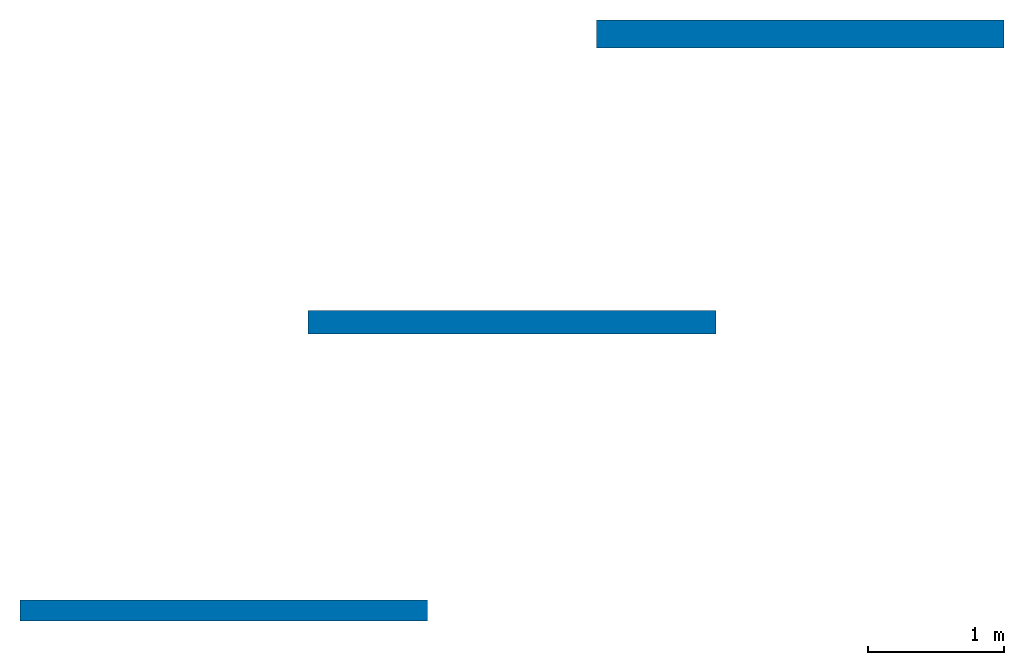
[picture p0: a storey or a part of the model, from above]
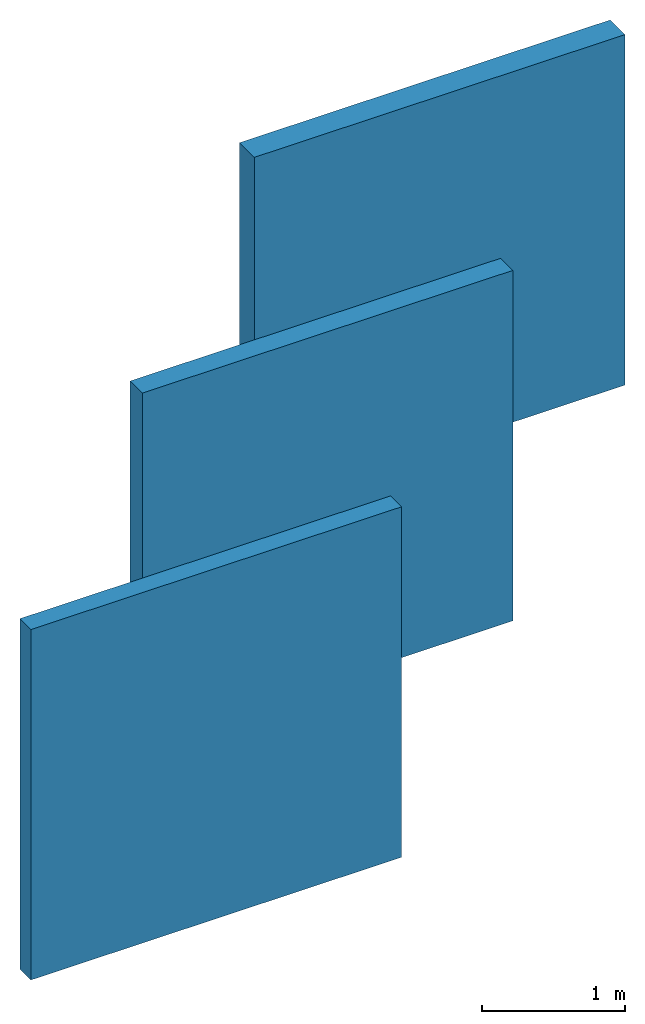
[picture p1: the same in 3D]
Properties of the parts of a building model (IFC2X3)

# File
Description: ViewDefinition [CoordinationView_V2.0, QuantityTakeOffAddOnView]
Time: 2021-05-19T20:20:58
Written by: The EXPRESS Data Manager Version 5.02.0100.07 : 28 Aug 2013
Made in: 20190108_1515(x64) - Exporter 19.1.0.0 - Alternate UI 19.1.0.0
Comment: STEP Physical File produced by: The EXPRESS Data Manager Version 5.02.0100.07 : 28 Aug 2013 * Module: EDMstepFileFactory/EDMstandAlone * Creation date: Wed May 19 20:20:58 2021 * Host: lt-026 * Database: C:\Users\WF2BF~1.POE\AppData\Local\Temp\{6B979DAE-2628-44FD-B715-F7CA476B2B23}\ifc * Database version: 5507 * Database creation date: Wed May 19 20:20:58 2021 * Schema: IFC2X3 * Model: DataRepository.ifc * Model creation date: Wed May 19 20:20:58 2021 * Header model: DataRepository.ifc_HeaderModel * Header model creation date: Wed May 19 20:20:58 2021 * EDMuser: sdai-user * EDMgroup: sdai-group * License ID and type: 5605 : Permanent license. Expiry date: * EDMstepFileFactory options: 020000

# IfcSite, Default
RefLatitude: 42, 24, 53, 508911; RefLongitude: -71, -15, -29, -58837; RefElevation: 0 mm
Other - Category: Project Information

# IfcBuilding
Pset_BuildingCommon - NumberOfStoreys: 1
Pset_ProductRequirements - Category: Project Information; sets with these values: 2

# IfcBuildingStorey: Level:NL_00_niveau, Begane grond
LongName: Begane grond; Elevation: 0 mm
Other(Type) - Category: Levels; Family Name: Level
Pset_AirSideSystemInformation - Name: Begane grond
Pset_ProductRequirements - Name: Begane grond; Category: Levels
Constraints - Elevation: 0 mm
Dimensions - Computation Height: 0 mm
Identity Data - Structural: no; Building Story: yes; Name: Begane grond
Other - Category: Levels; Family: Level: NL_00_niveau; Family and Type: Level: NL_00_niveau; Type: Level: NL_00_niveau; Type Id: Level: NL_00_niveau
Constraints(Type) - Elevation Base: Project Base Point
Graphics(Type) - Color: 16711680; Line Pattern: NL_00_niveau; Line Weight: 1; Symbol: NLRS_00_LAB_niveau bovenkant_gen_cadix: 1.8mm; Symbol at End 1 Default: no; Symbol at End 2 Default: yes
Identity Data(Type) - Type Name: NL_00_niveau

# IfcWallStandardCase: Basic Wall:NLRS_22_WA_Supafil Cavity XL_Spouwbreedte_154mm, Basic Wall:NLRS_22_WA_Supafil Cavity XL_Spouwbreedte_154mm:2470
In: Begane grond
Type - PredefinedType: STANDARD; Material: Knauf Insulation_inblaaswol Supafil Cavity XL 154 mm
Type - Analytical Properties - Absorptance: 0.1; Heat Transfer Coefficient (U): 0.24026; Roughness: 1; Thermal mass: 4533.76; Thermal Resistance (R): 4.16216
Type - Construction - Function: Exterior; Width: 154 mm; Wrapping at Inserts: Do not wrap
Type - Graphics - Coarse Scale Fill Color: 0
Type - Identity Data - Assembly Code: 22; Assembly Description: Binnenwanden; Description: Supafill Cavity XL; Manufacturer: Knauf Insulation B.V.; Model: Inblaas glaswol voor nieuwbouw woningen; Type Image: Raster image: SupafilCavityXL.png (2); Type Name: NLRS_22_WA_Supafil Cavity XL_Spouwbreedte_154mm; URL: www.knaufinsulation.nl
Type - Other - Category: Walls; Family Name: Basic Wall
Type - Pset_ElementShading - Roughness: 304.8 mm
Type - Pset_ManufacturerTypeInformation - Manufacturer: Knauf Insulation B.V.
Type - Pset_ProductRequirements - Category: Walls
Type - Pset_QuantityTakeOff - Reference: NLRS_22_WA_Supafil Cavity XL_Spouwbreedte_154mm
Type - Pset_ReinforcementBarPitchOfWall - Description: Supafill Cavity XL; Reference: NLRS_22_WA_Supafil Cavity XL_Spouwbreedte_154mm
Type - Pset_WallCommon - Reference: NLRS_22_WA_Supafil Cavity XL_Spouwbreedte_154mm; ThermalTransmittance: 0.24026 kg/K/s3; IsExternal: no
Classification: 22 Binnenwanden (Uniformat)
BaseQuantities - Height: 3000 mm; Length: 3000 mm; Width: 154 mm; GrossFootprintArea: 0.462 m2; NetVolume: 1386000000 m3; NetSideArea: 9000000 m2
Constraints - Base Constraint: Level: Begane grond; Base Extension Distance: 0 mm; Base is Attached: no; Base Offset: 0 mm; Location Line: Wall Centerline; Related to Mass: no; Room Bounding: yes; Top Constraint: Level: Hoogte; Top Extension Distance: 0 mm; Top is Attached: no; Top Offset: 0 mm; Unconnected Height: 3000 mm
Dimensions - Area: 9 m2; Length: 3000 mm; Volume: 1.386 m3
Other - Family: Basic Wall: NLRS_22_WA_Supafil Cavity XL_Spouwbreedte_154mm; Family and Type: Basic Wall: NLRS_22_WA_Supafil Cavity XL_Spouwbreedte_154mm; Type: Basic Wall: NLRS_22_WA_Supafil Cavity XL_Spouwbreedte_154mm; Type Id: Basic Wall: NLRS_22_WA_Supafil Cavity XL_Spouwbreedte_154mm
Phasing - Phase Created: New Construction
Structural - Enable Analytical Model: no; Structural: no; Structural Usage: Non-bearing
Pset_WallCommon - IsExternal: yes; ExtendToStructure: no; LoadBearing: no

# IfcWallStandardCase: Basic Wall:NLRS_22_WA_Supafil Cavity XL_Spouwbreedte_171mm, Basic Wall:NLRS_22_WA_Supafil Cavity XL_Spouwbreedte_171mm:3578
In: Begane grond
Type - PredefinedType: STANDARD; Material: Knauf Insulation_inblaaswol Supafil Cavity XL 171 mm
Type - Analytical Properties - Roughness: 1; Absorptance: 0.1; Heat Transfer Coefficient (U): 0.216374; Thermal mass: 5034.24; Thermal Resistance (R): 4.62162
Type - Construction - Function: Exterior; Wrapping at Inserts: Do not wrap; Width: 171 mm
Type - Graphics - Coarse Scale Fill Color: 0
Type - Identity Data - Type Image: Raster image: SupafilCavityXL.png (2); Assembly Code: 22; Assembly Description: Binnenwanden; Description: Supafill Cavity XL; Manufacturer: Knauf Insulation B.V.; Model: Inblaas glaswol voor nieuwbouw woningen; Type Name: NLRS_22_WA_Supafil Cavity XL_Spouwbreedte_171mm; URL: www.knaufinsulation.nl
Type - Other - Category: Walls; Family Name: Basic Wall
Type - Pset_ElementShading - Roughness: 304.8 mm
Type - Pset_ManufacturerTypeInformation - Manufacturer: Knauf Insulation B.V.
Type - Pset_ProductRequirements - Category: Walls
Type - Pset_QuantityTakeOff - Reference: NLRS_22_WA_Supafil Cavity XL_Spouwbreedte_171mm
Type - Pset_ReinforcementBarPitchOfWall - Description: Supafill Cavity XL; Reference: NLRS_22_WA_Supafil Cavity XL_Spouwbreedte_171mm
Type - Pset_WallCommon - IsExternal: no; Reference: NLRS_22_WA_Supafil Cavity XL_Spouwbreedte_171mm; ThermalTransmittance: 0.216374 kg/K/s3
Classification: 22 Binnenwanden (Uniformat)
BaseQuantities - Height: 3000 mm; Length: 3000 mm; Width: 171 mm; GrossFootprintArea: 0.513 m2; NetVolume: 1539000000 m3; NetSideArea: 9000000 m2
Constraints - Base Constraint: Level: Begane grond; Base Extension Distance: 0 mm; Base is Attached: no; Base Offset: 0 mm; Location Line: Wall Centerline; Related to Mass: no; Room Bounding: yes; Top Constraint: Level: Hoogte; Top Extension Distance: 0 mm; Top is Attached: no; Top Offset: 0 mm; Unconnected Height: 3000 mm
Dimensions - Area: 9 m2; Length: 3000 mm; Volume: 1.539 m3
Other - Family: Basic Wall: NLRS_22_WA_Supafil Cavity XL_Spouwbreedte_171mm; Family and Type: Basic Wall: NLRS_22_WA_Supafil Cavity XL_Spouwbreedte_171mm; Type: Basic Wall: NLRS_22_WA_Supafil Cavity XL_Spouwbreedte_171mm; Type Id: Basic Wall: NLRS_22_WA_Supafil Cavity XL_Spouwbreedte_171mm
Phasing - Phase Created: New Construction
Structural - Enable Analytical Model: no; Structural: no; Structural Usage: Non-bearing
Pset_WallCommon - IsExternal: yes; ExtendToStructure: no; LoadBearing: no

# IfcWallStandardCase: Basic Wall:NLRS_22_WA_Supafil Cavity XL_Spouwbreedte_207mm, Basic Wall:NLRS_22_WA_Supafil Cavity XL_Spouwbreedte_207mm:3605
In: Begane grond
Type - PredefinedType: STANDARD; Material: Knauf Insulation_inblaaswol Supafil Cavity XL 207 mm
Type - Analytical Properties - Roughness: 1; Absorptance: 0.1; Heat Transfer Coefficient (U): 0.178744; Thermal mass: 6094.08; Thermal Resistance (R): 5.59459
Type - Construction - Function: Exterior; Wrapping at Inserts: Do not wrap; Width: 207 mm
Type - Graphics - Coarse Scale Fill Color: 0
Type - Identity Data - Type Image: Raster image: SupafilCavityXL.png (2); Assembly Code: 22; Assembly Description: Binnenwanden; Description: Supafill Cavity XL; Manufacturer: Knauf Insulation B.V.; Model: Inblaas glaswol voor nieuwbouw woningen; Type Name: NLRS_22_WA_Supafil Cavity XL_Spouwbreedte_207mm; URL: www.knaufinsulation.nl
Type - Other - Category: Walls; Family Name: Basic Wall
Type - Pset_ElementShading - Roughness: 304.8 mm
Type - Pset_ManufacturerTypeInformation - Manufacturer: Knauf Insulation B.V.
Type - Pset_ProductRequirements - Category: Walls
Type - Pset_QuantityTakeOff - Reference: NLRS_22_WA_Supafil Cavity XL_Spouwbreedte_207mm
Type - Pset_ReinforcementBarPitchOfWall - Description: Supafill Cavity XL; Reference: NLRS_22_WA_Supafil Cavity XL_Spouwbreedte_207mm
Type - Pset_WallCommon - IsExternal: no; Reference: NLRS_22_WA_Supafil Cavity XL_Spouwbreedte_207mm; ThermalTransmittance: 0.178744 kg/K/s3
Classification: 22 Binnenwanden (Uniformat)
BaseQuantities - Height: 3000 mm; Length: 3000 mm; Width: 207 mm; GrossFootprintArea: 0.621 m2; NetVolume: 1863000000 m3; NetSideArea: 9000000 m2
Constraints - Base Constraint: Level: Begane grond; Base Extension Distance: 0 mm; Base is Attached: no; Base Offset: 0 mm; Location Line: Wall Centerline; Related to Mass: no; Room Bounding: yes; Top Constraint: Level: Hoogte; Top Extension Distance: 0 mm; Top is Attached: no; Top Offset: 0 mm; Unconnected Height: 3000 mm
Dimensions - Area: 9 m2; Length: 3000 mm; Volume: 1.863 m3
Other - Family: Basic Wall: NLRS_22_WA_Supafil Cavity XL_Spouwbreedte_207mm; Family and Type: Basic Wall: NLRS_22_WA_Supafil Cavity XL_Spouwbreedte_207mm; Type: Basic Wall: NLRS_22_WA_Supafil Cavity XL_Spouwbreedte_207mm; Type Id: Basic Wall: NLRS_22_WA_Supafil Cavity XL_Spouwbreedte_207mm
Phasing - Phase Created: New Construction
Structural - Enable Analytical Model: no; Structural: no; Structural Usage: Non-bearing
Pset_WallCommon - IsExternal: yes; ExtendToStructure: no; LoadBearing: no
